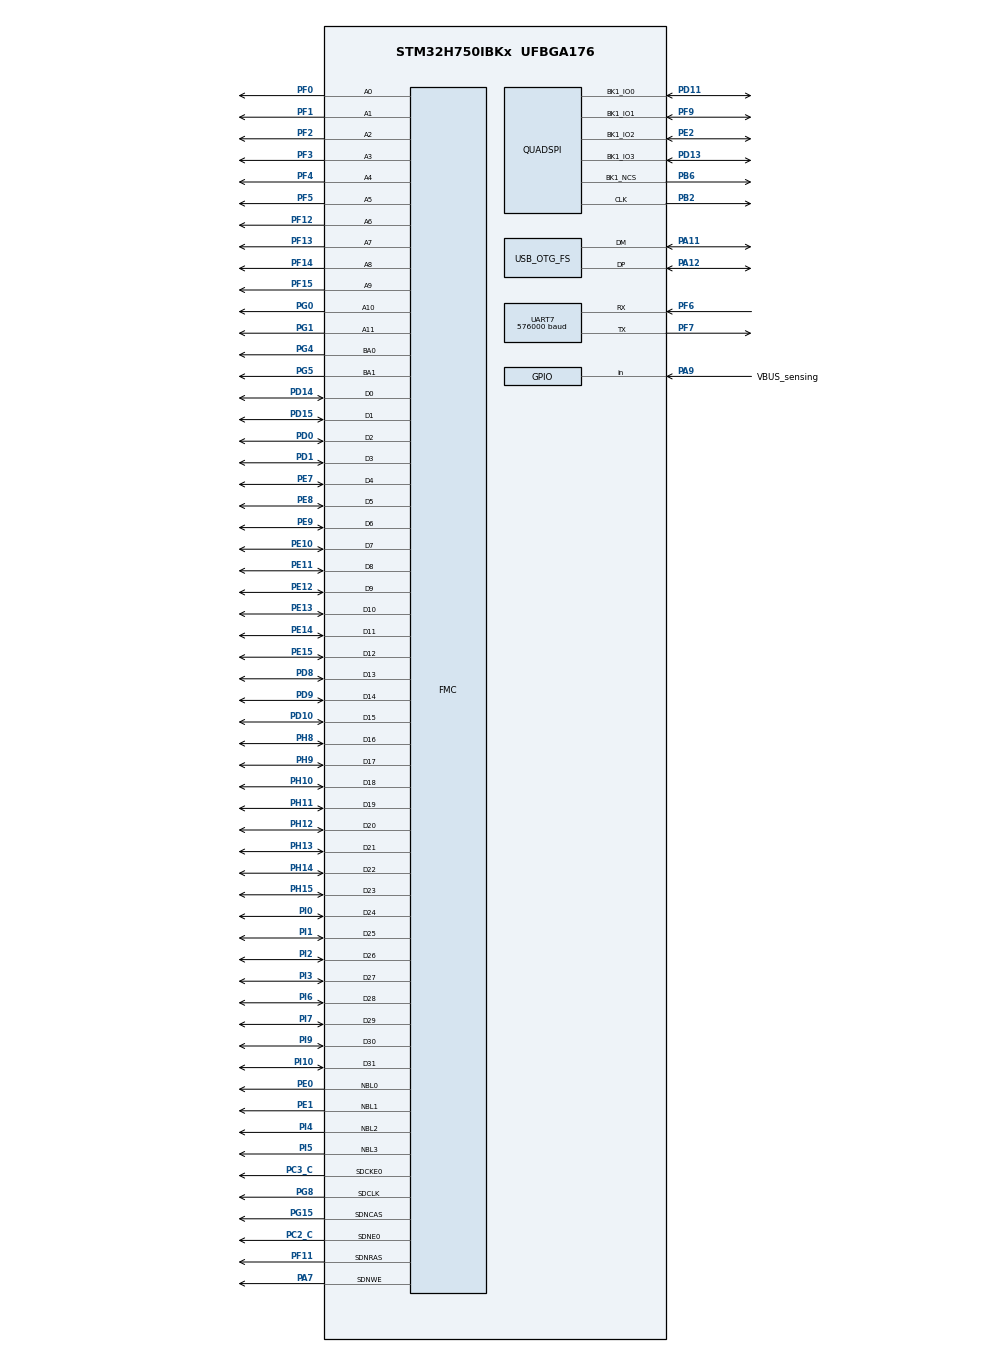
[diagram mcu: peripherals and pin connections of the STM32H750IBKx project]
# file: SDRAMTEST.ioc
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CORTEX_M7.AccessPermission_S-Cortex_Memory_Protection_Unit_Region1_Settings_S=MPU_REGION_FULL_ACCESS
CORTEX_M7.AccessPermission_Spec=MPU_REGION_FULL_ACCESS
CORTEX_M7.BaseAddress_S-Cortex_Memory_Protection_Unit_Region1_Settings_S=0x24000000
CORTEX_M7.BaseAddress_Spec=0xC0000000
CORTEX_M7.CPU_DCache=Enabled
CORTEX_M7.CPU_ICache=Enabled
CORTEX_M7.DisableExec_Spec=MPU_INSTRUCTION_ACCESS_ENABLE
CORTEX_M7.Enable_S-Cortex_Memory_Protection_Unit_Region1_Settings_S=MPU_REGION_ENABLE
CORTEX_M7.IsBufferable_Spec=MPU_ACCESS_NOT_BUFFERABLE
CORTEX_M7.IsCacheable_S-Cortex_Memory_Protection_Unit_Region1_Settings_S=MPU_ACCESS_CACHEABLE
CORTEX_M7.IsCacheable_Spec=MPU_ACCESS_CACHEABLE
CORTEX_M7.IsShareable_Spec=MPU_ACCESS_NOT_SHAREABLE
CORTEX_M7.MPU_Control=MPU_PRIVILEGED_DEFAULT
CORTEX_M7.Size_S-Cortex_Memory_Protection_Unit_Region1_Settings_S=MPU_REGION_SIZE_512KB
CORTEX_M7.Size_Spec=MPU_REGION_SIZE_256MB
CORTEX_M7.SubRegionDisable_Spec=0x00
CORTEX_M7.default_mode_Activation=1
Dma.Request0=UART7_TX
Dma.UART7_TX.0.Direction=DMA_MEMORY_TO_PERIPH
Dma.UART7_TX.0.EventEnable=DISABLE
Dma.UART7_TX.0.FIFOMode=DMA_FIFOMODE_DISABLE
Dma.UART7_TX.0.Instance=DMA1_Stream0
Dma.UART7_TX.0.MemDataAlignment=DMA_MDATAALIGN_BYTE
Dma.UART7_TX.0.MemInc=DMA_MINC_ENABLE
Dma.UART7_TX.0.Mode=DMA_NORMAL
Dma.UART7_TX.0.PeriphDataAlignment=DMA_PDATAALIGN_BYTE
Dma.UART7_TX.0.PeriphInc=DMA_PINC_DISABLE
Dma.UART7_TX.0.Polarity=HAL_DMAMUX_REQ_GEN_RISING
Dma.UART7_TX.0.Priority=DMA_PRIORITY_LOW
Dma.UART7_TX.0.RequestNumber=1
Dma.UART7_TX.0.SignalID=NONE
Dma.UART7_TX.0.SyncEnable=DISABLE
Dma.UART7_TX.0.SyncPolarity=HAL_DMAMUX_SYNC_NO_EVENT
Dma.UART7_TX.0.SyncRequestNumber=1
Dma.UART7_TX.0.SyncSignalID=NONE
FMC.CASLatency1=FMC_SDRAM_CAS_LATENCY_3
FMC.ColumnBitsNumber1=FMC_SDRAM_COLUMN_BITS_NUM_9
FMC.ExitSelfRefreshDelay1=7
FMC.LoadToActiveDelay1=2
FMC.RCDDelay1=2
FMC.RPDelay1=2
FMC.ReadBurst1=FMC_SDRAM_RBURST_ENABLE
FMC.ReadPipeDelay1=FMC_SDRAM_RPIPE_DELAY_1
FMC.ReadPipeDelay2=FMC_SDRAM_RPIPE_DELAY_1
FMC.RowCycleDelay1=7
FMC.SDClockPeriod1=FMC_SDRAM_CLOCK_PERIOD_2
FMC.SelfRefreshTime1=4
FMC.WriteRecoveryTime1=3
Mcu.Family=STM32H7
Mcu.Name=STM32H750IBKx
Mcu.Package=UFBGA176
NVIC.DMA1_Stream0_IRQn=true\:0\:0\:false\:false\:true\:false\:true\:true
NVIC.OTG_FS_IRQn=true\:0\:0\:false\:false\:true\:false\:true\:true
NVIC.PriorityGroup=NVIC_PRIORITYGROUP_4
NVIC.UART7_IRQn=true\:0\:0\:false\:false\:true\:true\:true\:true
PA11.Mode=Device_Only
PA11.Signal=USB_OTG_FS_DM
PA12.Mode=Device_Only
PA12.Signal=USB_OTG_FS_DP
PA13\ (JTMS/SWDIO).Mode=Serial_Wire
PA13\ (JTMS/SWDIO).Signal=DEBUG_JTMS-SWDIO
PA14\ (JTCK/SWCLK).Mode=Serial_Wire
PA14\ (JTCK/SWCLK).Signal=DEBUG_JTCK-SWCLK
PA7.Signal=FMC_SDNWE
PA9.GPIO_Label=VBUS_sensing
PA9.Signal=GPIO_Input
PB2.GPIO_Speed=GPIO_SPEED_FREQ_VERY_HIGH
PB2.Mode=Single Bank 1
PB2.Signal=QUADSPI_CLK
PB6.GPIO_Speed=GPIO_SPEED_FREQ_VERY_HIGH
PB6.Mode=Single Bank 1
PB6.Signal=QUADSPI_BK1_NCS
PC2_C.Mode=SdramChipSelect1_1
PC2_C.Signal=FMC_SDNE0
PC3_C.Mode=SdramChipSelect1_1
PC3_C.Signal=FMC_SDCKE0
PD0.Signal=FMC_D2_DA2
PD1.Signal=FMC_D3_DA3
PD10.Signal=FMC_D15_DA15
PD11.GPIO_Speed=GPIO_SPEED_FREQ_VERY_HIGH
PD11.Mode=Single Bank 1
PD11.Signal=QUADSPI_BK1_IO0
PD13.GPIO_Speed=GPIO_SPEED_FREQ_VERY_HIGH
PD13.Mode=Single Bank 1
PD13.Signal=QUADSPI_BK1_IO3
PD14.Signal=FMC_D0_DA0
PD15.Signal=FMC_D1_DA1
PD8.Signal=FMC_D13_DA13
PD9.Signal=FMC_D14_DA14
PE0.Signal=FMC_NBL0
PE1.Signal=FMC_NBL1
PE10.Signal=FMC_D7_DA7
PE11.Signal=FMC_D8_DA8
PE12.Signal=FMC_D9_DA9
PE13.Signal=FMC_D10_DA10
PE14.Signal=FMC_D11_DA11
PE15.Signal=FMC_D12_DA12
PE2.GPIO_Speed=GPIO_SPEED_FREQ_VERY_HIGH
PE2.Mode=Single Bank 1
PE2.Signal=QUADSPI_BK1_IO2
PE7.Signal=FMC_D4_DA4
PE8.Signal=FMC_D5_DA5
PE9.Signal=FMC_D6_DA6
PF0.Signal=FMC_A0
PF1.Signal=FMC_A1
PF11.Signal=FMC_SDNRAS
PF12.Signal=FMC_A6
PF13.Signal=FMC_A7
PF14.Signal=FMC_A8
PF15.Signal=FMC_A9
PF2.Signal=FMC_A2
PF3.Signal=FMC_A3
PF4.Signal=FMC_A4
PF5.Signal=FMC_A5
PF6.Mode=Asynchronous
PF6.Signal=UART7_RX
PF7.Mode=Asynchronous
PF7.Signal=UART7_TX
PF9.GPIO_Speed=GPIO_SPEED_FREQ_VERY_HIGH
PF9.Mode=Single Bank 1
PF9.Signal=QUADSPI_BK1_IO1
PG0.Signal=FMC_A10
PG1.Signal=FMC_A11
PG15.Signal=FMC_SDNCAS
PG4.Signal=FMC_A14_BA0
PG5.Signal=FMC_A15_BA1
PG8.Signal=FMC_SDCLK
PH0-OSC_IN\ (PH0).Mode=HSE-External-Oscillator
PH0-OSC_IN\ (PH0).Signal=RCC_OSC_IN
PH1-OSC_OUT\ (PH1).Mode=HSE-External-Oscillator
PH1-OSC_OUT\ (PH1).Signal=RCC_OSC_OUT
PH10.Signal=FMC_D18
PH11.Signal=FMC_D19
PH12.Signal=FMC_D20
PH13.Signal=FMC_D21
PH14.Signal=FMC_D22
PH15.Signal=FMC_D23
PH8.Signal=FMC_D16
PH9.Signal=FMC_D17
PI0.Signal=FMC_D24
PI1.Signal=FMC_D25
PI10.Signal=FMC_D31
PI2.Signal=FMC_D26
PI3.Signal=FMC_D27
PI4.Signal=FMC_NBL2
PI5.Signal=FMC_NBL3
PI6.Signal=FMC_D28
PI7.Signal=FMC_D29
PI9.Signal=FMC_D30
ProjectManager.HeapSize=0x800
ProjectManager.StackSize=0x800
ProjectManager.TargetToolchain=MDK-ARM V5.32
QUADSPI.ClockPrescaler=2-1
QUADSPI.FlashSize=8-1
RCC.ADCFreq_Value=64500000
RCC.APB1Freq_Value=60000000
RCC.APB2Freq_Value=60000000
RCC.APB3Freq_Value=60000000
RCC.APB4Freq_Value=60000000
RCC.CortexFreq_Value=240000000
RCC.D1PPRE=RCC_APB3_DIV2
RCC.D2PPRE1=RCC_APB1_DIV2
RCC.D2PPRE2=RCC_APB2_DIV2
RCC.D3PPRE=RCC_APB4_DIV2
RCC.DIVM1=3
RCC.DIVM2=24
RCC.DIVM3=24
RCC.DIVN1=60
RCC.DIVN3=192
RCC.DIVQ3=4
RCC.HCLKFreq_Value=120000000
RCC.HPRE=RCC_HCLK_DIV2
RCC.HSE_VALUE=24000000
RCC.PLLSourceVirtual=RCC_PLLSOURCE_HSE
RCC.ProductRev=revV
RCC.SYSCLKFreq_VALUE=240000000
RCC.SYSCLKSource=RCC_SYSCLKSOURCE_PLLCLK
RCC.USBCLockSelection=RCC_USBCLKSOURCE_PLL3
RCC.USBFreq_Value=48000000
SH.FMC_A0.0=FMC_A0,12b-sda1
SH.FMC_A1.0=FMC_A1,12b-sda1
SH.FMC_A10.0=FMC_A10,12b-sda1
SH.FMC_A11.0=FMC_A11,12b-sda1
SH.FMC_A14_BA0.0=FMC_BA0,FourSdramBanks1
SH.FMC_A15_BA1.0=FMC_BA1,FourSdramBanks1
SH.FMC_A2.0=FMC_A2,12b-sda1
SH.FMC_A3.0=FMC_A3,12b-sda1
SH.FMC_A4.0=FMC_A4,12b-sda1
SH.FMC_A5.0=FMC_A5,12b-sda1
SH.FMC_A6.0=FMC_A6,12b-sda1
SH.FMC_A7.0=FMC_A7,12b-sda1
SH.FMC_A8.0=FMC_A8,12b-sda1
SH.FMC_A9.0=FMC_A9,12b-sda1
SH.FMC_D0_DA0.0=FMC_D0,sd-32b-d1
SH.FMC_D10_DA10.0=FMC_D10,sd-32b-d1
SH.FMC_D11_DA11.0=FMC_D11,sd-32b-d1
SH.FMC_D12_DA12.0=FMC_D12,sd-32b-d1
SH.FMC_D13_DA13.0=FMC_D13,sd-32b-d1
SH.FMC_D14_DA14.0=FMC_D14,sd-32b-d1
SH.FMC_D15_DA15.0=FMC_D15,sd-32b-d1
SH.FMC_D16.0=FMC_D16,sd-32b-d1
SH.FMC_D17.0=FMC_D17,sd-32b-d1
SH.FMC_D18.0=FMC_D18,sd-32b-d1
SH.FMC_D19.0=FMC_D19,sd-32b-d1
SH.FMC_D1_DA1.0=FMC_D1,sd-32b-d1
SH.FMC_D20.0=FMC_D20,sd-32b-d1
SH.FMC_D21.0=FMC_D21,sd-32b-d1
SH.FMC_D22.0=FMC_D22,sd-32b-d1
SH.FMC_D23.0=FMC_D23,sd-32b-d1
SH.FMC_D24.0=FMC_D24,sd-32b-d1
SH.FMC_D25.0=FMC_D25,sd-32b-d1
SH.FMC_D26.0=FMC_D26,sd-32b-d1
SH.FMC_D27.0=FMC_D27,sd-32b-d1
SH.FMC_D28.0=FMC_D28,sd-32b-d1
SH.FMC_D29.0=FMC_D29,sd-32b-d1
SH.FMC_D2_DA2.0=FMC_D2,sd-32b-d1
SH.FMC_D30.0=FMC_D30,sd-32b-d1
SH.FMC_D31.0=FMC_D31,sd-32b-d1
SH.FMC_D3_DA3.0=FMC_D3,sd-32b-d1
SH.FMC_D4_DA4.0=FMC_D4,sd-32b-d1
SH.FMC_D5_DA5.0=FMC_D5,sd-32b-d1
SH.FMC_D6_DA6.0=FMC_D6,sd-32b-d1
SH.FMC_D7_DA7.0=FMC_D7,sd-32b-d1
SH.FMC_D8_DA8.0=FMC_D8,sd-32b-d1
SH.FMC_D9_DA9.0=FMC_D9,sd-32b-d1
SH.FMC_NBL0.0=FMC_NBL0,Sd4ByteEnable1
SH.FMC_NBL1.0=FMC_NBL1,Sd4ByteEnable1
SH.FMC_NBL2.0=FMC_NBL2,Sd4ByteEnable1
SH.FMC_NBL3.0=FMC_NBL3,Sd4ByteEnable1
SH.FMC_SDCLK.0=FMC_SDCLK,12b-sda1
SH.FMC_SDNCAS.0=FMC_SDNCAS,12b-sda1
SH.FMC_SDNRAS.0=FMC_SDNRAS,12b-sda1
SH.FMC_SDNWE.0=FMC_SDNWE,12b-sda1
UART7.BaudRate=576000
USB_DEVICE.CLASS_NAME_FS=DFU
USB_DEVICE.PRODUCT_STRING_DFU_FS=STM32 H750IB DFU
USB_DEVICE.USBD_DEBUG_LEVEL-DFU_FS=0
USB_DEVICE.USBD_DFU_APP_DEFAULT_ADD-DFU_FS=0x08020000
USB_DEVICE.USBD_DFU_MEDIA-DFU_FS=@Internal Flash   /0x08000000/1*128Ka,15*128Kg   @External FLASH   /0x90000000/128*64Kg
USB_DEVICE.USBD_MAX_STR_DESC_SIZ-DFU_FS=1024
USB_DEVICE.VirtualMode-DFU_FS=Dfu
USB_DEVICE.VirtualModeFS=Dfu_FS
USB_OTG_FS.VirtualMode=Device_Only
VP_USB_DEVICE_VS_USB_DEVICE_DFU_FS.Mode=DFU_FS
board=custom

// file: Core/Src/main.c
/* USER CODE BEGIN Header */
/**
 ******************************************************************************
 * @file           : main.c
 * @brief          : Main program body
 ******************************************************************************
 * @attention
 *
 * Copyright (c) 2023 STMicroelectronics.
 * All rights reserved.
 *
 * This software is licensed under terms that can be found in the LICENSE file
 * in the root directory of this software component.
 * If no LICENSE file comes with this software, it is provided AS-IS.
 *
 ******************************************************************************
 */
/* USER CODE END Header */
#include "main.h"
#include "dma.h"
#include "quadspi.h"
#include "usart.h"
#include "usb_device.h"
#include "gpio.h"
#include "fmc.h"

/* USER CODE BEGIN Includes */
#include "qspi_w25q64.h"
/* USER CODE END Includes */

/* USER CODE BEGIN PD */
//#define APP_ADDR (0x90000000U)
#define APP_ADDR (0x08020000U)
/* USER CODE END PD */

/* USER CODE BEGIN PV */
typedef void (*pFunction)(void);
/* USER CODE END PV */

void SystemClock_Config(void);
static void MPU_Config(void);

/* USER CODE BEGIN 0 */
int fputc(int ch, FILE *f)
{
  HAL_UART_Transmit(&huart7, (uint8_t *)&ch, 1, 10); // ·?????×???????
  return (ch);
}

volatile uint8_t jump_flag = 0;
void set_jump2app_flag()
{
  jump_flag = 1;
}

void jump2app()
{
  if (jump_flag == 1)
  {
    QSPI_W25Qxx_MemoryMappedMode(); // 内存映射模式 ********在APP中无需再次配置QSPI********

    pFunction JumpToApplication;
    uint32_t JumpAddress;
    /* Test if user code is programmed starting from USBD_DFU_APP_DEFAULT_ADD address */
    // if (((*(__IO uint32_t *)USBD_DFU_APP_DEFAULT_ADD) & 0x2FFE0000) == 0x20000000)
    {
      /* Jump to user application */
      JumpAddress = *(__IO uint32_t *)(APP_ADDR + 4);
      JumpToApplication = (pFunction)JumpAddress;

      /* Initialize user application's Stack Pointer */
      SysTick->CTRL &= ~1;
      SysTick->CTRL &= ~SysTick_CTRL_COUNTFLAG_Msk;
      __set_MSP(*(__IO uint32_t *)APP_ADDR);
      __disable_irq(); // 此处官方代码未放置关闭中断，在跳转app的时候会出问题！！！！！??
      JumpToApplication();
    }
  }
}

/* USER CODE END 0 */

int main(void)
{

  /* MPU Configuration--------------------------------------------------------*/
  MPU_Config();

  /* Enable I-Cache---------------------------------------------------------*/
  SCB_EnableICache();

  /* Enable D-Cache---------------------------------------------------------*/
  SCB_EnableDCache();

  /* MCU Configuration--------------------------------------------------------*/

  /* Reset of all peripherals, Initializes the Flash interface and the Systick. */
  HAL_Init();

  /* Configure the system clock */
  SystemClock_Config();

  /* Initialize all configured peripherals */
  MX_GPIO_Init();
  MX_DMA_Init();
  // MX_FMC_Init();
  MX_UART7_Init();
  MX_USB_DEVICE_Init();
  // MX_QUADSPI_Init();
  /* USER CODE BEGIN 2 */
  __NVIC_SetPriority(SysTick_IRQn, 0);
  __NVIC_SetPriority(OTG_FS_IRQn, 2);

  QSPI_W25Qxx_Init();
  // QSPI_W25Qxx_MemoryMappedMode();
  if (HAL_GPIO_ReadPin(VBUS_sensing_GPIO_Port, VBUS_sensing_Pin) == GPIO_PIN_RESET) // 判断VBUS引脚有没有电压，如果没有则无需等待USB直接跳转APP
    set_jump2app_flag();
  else
  {
    HAL_Delay(1000);                                  // 延时1s，USB识别需要时间
    if (hUsbDeviceFS.dev_state == USBD_STATE_DEFAULT) // USB处于默认状态时说明没有连接到USB HOST，进入APP模式
    {
      set_jump2app_flag();
    }
  }
  /* USER CODE END 2 */

  /* Infinite loop */
  /* USER CODE BEGIN WHILE */
  while (1)
  {
    jump2app();
    /* USER CODE END WHILE */

  }
}

void SystemClock_Config(void)
{
  RCC_OscInitTypeDef RCC_OscInitStruct = {0};
  RCC_ClkInitTypeDef RCC_ClkInitStruct = {0};

  /** Supply configuration update enable
   */
  HAL_PWREx_ConfigSupply(PWR_LDO_SUPPLY);

  /** Configure the main internal regulator output voltage
   */
  __HAL_PWR_VOLTAGESCALING_CONFIG(PWR_REGULATOR_VOLTAGE_SCALE2);

  while (!__HAL_PWR_GET_FLAG(PWR_FLAG_VOSRDY))
  {
  }

  /** Macro to configure the PLL clock source
   */
  __HAL_RCC_PLL_PLLSOURCE_CONFIG(RCC_PLLSOURCE_HSE);

  /** Initializes the RCC Oscillators according to the specified parameters
   * in the RCC_OscInitTypeDef structure.
   */
  RCC_OscInitStruct.OscillatorType = RCC_OSCILLATORTYPE_HSE;
  RCC_OscInitStruct.HSEState = RCC_HSE_ON;
  RCC_OscInitStruct.PLL.PLLState = RCC_PLL_ON;
  RCC_OscInitStruct.PLL.PLLSource = RCC_PLLSOURCE_HSE;
  RCC_OscInitStruct.PLL.PLLM = 3;
  RCC_OscInitStruct.PLL.PLLN = 120;
  RCC_OscInitStruct.PLL.PLLP = 2;
  RCC_OscInitStruct.PLL.PLLQ = 2;
  RCC_OscInitStruct.PLL.PLLR = 2;
  RCC_OscInitStruct.PLL.PLLRGE = RCC_PLL1VCIRANGE_3;
  RCC_OscInitStruct.PLL.PLLVCOSEL = RCC_PLL1VCOWIDE;
  RCC_OscInitStruct.PLL.PLLFRACN = 0;
  if (HAL_RCC_OscConfig(&RCC_OscInitStruct) != HAL_OK)
  {
    Error_Handler();
  }

  /** Initializes the CPU, AHB and APB buses clocks
   */
  RCC_ClkInitStruct.ClockType = RCC_CLOCKTYPE_HCLK | RCC_CLOCKTYPE_SYSCLK | RCC_CLOCKTYPE_PCLK1 | RCC_CLOCKTYPE_PCLK2 | RCC_CLOCKTYPE_D3PCLK1 | RCC_CLOCKTYPE_D1PCLK1;
  RCC_ClkInitStruct.SYSCLKSource = RCC_SYSCLKSOURCE_PLLCLK;
  RCC_ClkInitStruct.SYSCLKDivider = RCC_SYSCLK_DIV1;
  RCC_ClkInitStruct.AHBCLKDivider = RCC_HCLK_DIV2;
  RCC_ClkInitStruct.APB3CLKDivider = RCC_APB3_DIV2;
  RCC_ClkInitStruct.APB1CLKDivider = RCC_APB1_DIV2;
  RCC_ClkInitStruct.APB2CLKDivider = RCC_APB2_DIV2;
  RCC_ClkInitStruct.APB4CLKDivider = RCC_APB4_DIV2;

  if (HAL_RCC_ClockConfig(&RCC_ClkInitStruct, FLASH_LATENCY_2) != HAL_OK)
  {
    Error_Handler();
  }
}

/* MPU Configuration */

void MPU_Config(void)
{
  MPU_Region_InitTypeDef MPU_InitStruct = {0};

  /* Disables the MPU */
  HAL_MPU_Disable();

  /** Initializes and configures the Region and the memory to be protected
   */
  MPU_InitStruct.Enable = MPU_REGION_ENABLE;
  MPU_InitStruct.Number = MPU_REGION_NUMBER0;
  MPU_InitStruct.BaseAddress = 0xC0000000;
  MPU_InitStruct.Size = MPU_REGION_SIZE_256MB;
  MPU_InitStruct.SubRegionDisable = 0x00;
  MPU_InitStruct.TypeExtField = MPU_TEX_LEVEL0;
  MPU_InitStruct.AccessPermission = MPU_REGION_FULL_ACCESS;
  MPU_InitStruct.DisableExec = MPU_INSTRUCTION_ACCESS_ENABLE;
  MPU_InitStruct.IsShareable = MPU_ACCESS_NOT_SHAREABLE;
  MPU_InitStruct.IsCacheable = MPU_ACCESS_CACHEABLE;
  MPU_InitStruct.IsBufferable = MPU_ACCESS_NOT_BUFFERABLE;

  HAL_MPU_ConfigRegion(&MPU_InitStruct);

  /** Initializes and configures the Region and the memory to be protected
   */
  MPU_InitStruct.Number = MPU_REGION_NUMBER1;
  MPU_InitStruct.BaseAddress = 0x24000000;
  MPU_InitStruct.Size = MPU_REGION_SIZE_512KB;
  MPU_InitStruct.SubRegionDisable = 0x0;

  HAL_MPU_ConfigRegion(&MPU_InitStruct);
  /* Enables the MPU */
  HAL_MPU_Enable(MPU_PRIVILEGED_DEFAULT);
}

void Error_Handler(void)
{
  __disable_irq();
  while (1)
  {
  }
}
